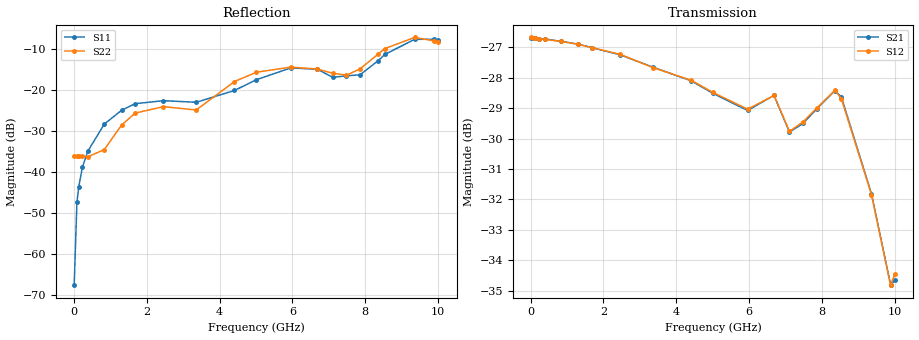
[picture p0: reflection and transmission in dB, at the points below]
! Device ID: PE43704
! Dir: z:\PE43704\PE43704_Char_1_20130516\PE43704\AMB\3p400V\25p75dB
! Serial: 14
! Insertion: A
! Impedance: 50 ohm
! Temp: Amb
! VDD: 3.400V
! Attenuation Step: 25.75dB
! IDD: 1.140438e-01mA
#  Hz  S  RI  R  50
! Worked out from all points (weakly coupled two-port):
!   401 points, 10 MHz to 10.01 GHz, reference 50 ohm
!   highest |S21| = -26.68 dB at 10 MHz (marker M1); lowest = -34.8 dB at 9.885 GHz (marker M2)
!   lowest |S11| = -67.5 dB at 10 MHz (marker M3), VSWR 1.00, Z = 50 + j0.0412 ohm
!   |S11| at or under -10 dB: start of sweep to 8.736 GHz
!   |S22| runs from -36.3 to -7.2 dB; largest |S21 - S12| = 0.00086
!   S11 on the Smith chart (normalised r, x): 10 MHz: 1.00, +0.00; 7.485 GHz: 0.78, +0.15; 8.535 GHz: 0.79, +0.45; 9.36 GHz: 0.54, +0.48; 10.01 GHz: 0.46, +0.27
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1e7  -8.18e-05 0.000413  0.0463 -0.000137  0.0464 -0.000138  0.0155 0.000215
8.5e7  -5.22e-06 0.00433  0.0462 -0.00106  0.0462 -0.00106  0.0155 0.0028
1.35e8  -0.00019 0.00661  0.0462 -0.00168  0.0462 -0.00164  0.0151 0.00448
2.35e8  -0.00184 0.0113  0.0461 -0.00281  0.0461 -0.00281  0.0134 0.00786
3.85e8  -0.00494 0.0173  0.0459 -0.00463  0.0458 -0.00463  0.00997 0.0117
8.35e8  -0.0251 0.0289  0.0447 -0.00955  0.0447 -0.00955  -0.00964 0.0161
1.31e9  -0.0504 0.0256  0.0428 -0.0146  0.0428 -0.0145  -0.0368 0.0062
1.685e9  -0.0663 0.015  0.0408 -0.0181  0.0408 -0.0181  -0.0517 -0.00811
2.46e9  -0.0737 -0.00639  0.0358 -0.0246  0.0359 -0.0246  -0.0571 -0.0256
3.36e9  -0.0707 -0.000779  0.0285 -0.0301  0.0285 -0.03  -0.0569 -0.00318
4.41e9  -0.0884 0.0434  0.0205 -0.0336  0.0205 -0.0337  -0.1148 0.0533
5.01e9  -0.1121 0.0719  0.0163 -0.0338  0.0164 -0.0339  -0.1501 0.0663
5.96e9  -0.1595 0.0947  0.00939 -0.0339  0.00967 -0.034  -0.1727 0.0779
6.685e9  -0.1593 0.0803  0.00583 -0.0368  0.00567 -0.0368  -0.1569 0.0872
7.11e9  -0.1287 0.0612  -0.000106 -0.0324  -0.000213 -0.0325  -0.117 0.1083
7.485e9  -0.1152 0.0934  0.000296 -0.0335  0.000446 -0.0337  -0.0813 0.1274
7.86e9  -0.0705 0.1359  -0.000583 -0.0354  -0.000709 -0.0355  -0.0596 0.1704
8.36e9  -0.0407 0.2239  -0.00958 -0.0367  -0.00943 -0.0368  -0.066 0.266
8.535e9  -0.0492 0.2659  -0.0129 -0.0347  -0.0127 -0.0345  -0.0804 0.308
9.36e9  -0.1872 0.368  -0.0157 -0.0203  -0.0157 -0.0202  -0.2079 0.3832
9.885e9  -0.3041 0.2805  -0.00692 -0.0168  -0.00734 -0.0166  -0.2989 0.2592
1.001e10  -0.3239 0.2413  -0.00422 -0.018  -0.00453 -0.0184  -0.3127 0.2155
